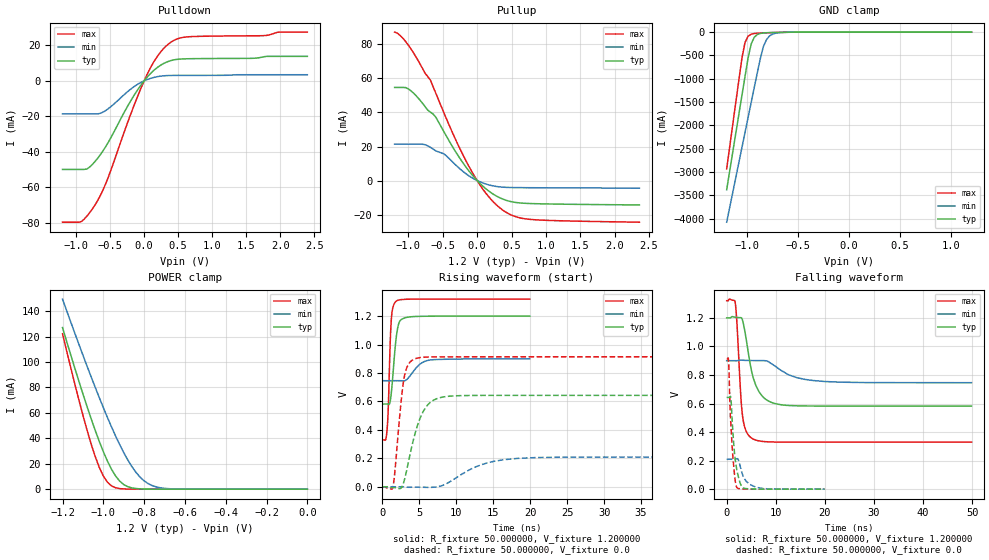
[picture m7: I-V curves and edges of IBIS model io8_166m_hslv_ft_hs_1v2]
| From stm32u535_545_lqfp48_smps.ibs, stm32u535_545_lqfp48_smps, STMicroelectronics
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|   Model io8_166m_hslv_ft_hs_1v2
[Model]  io8_166m_hslv_ft_hs_1v2
Model_type I/O
Polarity   Non-Inverting
Enable   Active-Low
Vinl =   0.360000V
Vinh =   0.840000V
Vmeas =  0.600000V
Cref =   50.000000pF
Rref =   100.000000M
Vref =   0.0V
C_comp   3.151700pF   3.087200pF   3.197900pF
[Temperature Range]   25.000000   0.140000k   -40.000000
[Pullup Reference]   1.200000V   0.900000V   1.320000V
[Pulldown Reference]   0.0V   0.0V   0.0V
[POWER Clamp Reference]   1.200000V   0.900000V   1.320000V
[GND Clamp Reference]   0.0V   0.0V   0.0V
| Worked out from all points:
|   slope of the pulldown table from 0 to 0.18 V, typ, clamps not added: 25.4 ohm
|   slope of the pullup table from 0 to 0.18 V, typ, clamps not added: 27.8 ohm
|   GND clamp passes 1 mA (typ) near -0.51 V on its own axis
|   POWER clamp passes 1 mA (typ) near -0.86 V on its own axis
|   rising waveform, R_fixture 50.000000, V_fixture 1.200000: 20-80 % time 648ps typ, 1.58ns min, 370ps max; typ from 0.582 V to 1.2 V
|   rising waveform, R_fixture 50.000000, V_fixture 0.0: 20-80 % time 2.05ns typ, 4.82ns min, 1.01ns max; typ from 0 V to 0.643 V
|   falling waveform, R_fixture 50.000000, V_fixture 1.200000: 20-80 % time 2.39ns typ, 5.33ns min, 1.03ns max; typ from 1.2 V to 0.582 V
|   falling waveform, R_fixture 50.000000, V_fixture 0.0: 20-80 % time 1.04ns typ, 1.73ns min, 825ps max; typ from 0.643 V to 0 V
[Pulldown]
|Voltage   I(typ)   I(min)   I(max)
-1.2V     -49.86mA   -18.57mA   -79.57mA
-920mV    -49.86mA   -18.57mA   -79.2mA
-840mV    -49.6mA    -18.57mA   -76.08mA
-720mV    -45.32mA   -18.57mA   -69.74mA
-560mV    -36.71mA   -16.58mA   -57.44mA
-200mV    -11.43mA   -4.74mA    -19.03mA
0V        10fA       -600fA     0A
160mV     6.477mA    2.075mA    11.78mA
360mV     10.99mA    2.99mA     20.81mA
480mV     12.07mA    3.054mA    23.53mA
640mV     12.43mA    3.075mA    24.76mA
2.4V      13.79mA    3.434mA    27.44mA
[Pullup]
|Voltage   I(typ)   I(min)   I(max)
-1.2V     54.73mA    21.36mA    87.24mA
-1.04V    54.63mA    21.36mA    81.73mA
-880mV    49.52mA    21.36mA    72.02mA
-680mV    40.23mA    19.54mA    59.03mA
-600mV    37.18mA    17.44mA    51.24mA
-480mV    28.49mA    15.58mA    39.53mA
-80mV     3.667mA    1.75mA     5.47mA
120mV     -4.592mA   -1.936mA   -7.077mA
360mV     -10.68mA   -3.85mA    -16.99mA
560mV     -12.87mA   -4.135mA   -21.24mA
760mV     -13.48mA   -4.204mA   -22.78mA
2.36V     -14.3mA    -4.5mA     -24.47mA
[GND_clamp]
|Voltage   I(typ)   I(min)   I(max)
-1.2V     -3.379A    -4.076A    -2.932A
-1.05V    -1.35A     -2.47A     -550.7mA
-1.02V    -947.8mA   -2.149A    -221.5mA
-990mV    -552.4mA   -1.829A    -88.44mA
-960mV    -255.3mA   -1.51A     -44.87mA
-930mV    -111.8mA   -1.191A    -30.68mA
-870mV    -28.36mA   -564.6mA   -21.34mA
-840mV    -18.65mA   -309.5mA   -18.49mA
-810mV    -14.07mA   -161.6mA   -15.92mA
-780mV    -11.37mA   -83.33mA   -13.53mA
-600mV    -3.009mA   -4.322mA   -3.091mA
1.2V      0A         13.65nA    0A
[POWER_clamp]
|Voltage   I(typ)   I(min)   I(max)
-1.2V     127mA      149.4mA    122.2mA
-1.12V    84.97mA    114mA      70.27mA
-1.06V    55.51mA    88.42mA    35.67mA
-1.02V    37.63mA    72.04mA    17.17mA
-1V       29.51mA    64.13mA    10.3mA
-960mV    15.69mA    48.99mA    2.571mA
-900mV    3.624mA    28.77mA    182.8uA
-840mV    490.7uA    13.24mA    11.35uA
-800mV    116.8uA    6.532mA    1.77uA
-740mV    13.2uA     1.723mA    109.1nA
-620mV    167.4nA    79.36uA    0A
0V        0A         17.87nA    0A
[Ramp]
| variable   typ   min   max
dV/dt_r  0.38563/2.04306n   0.12552/4.81423n   0.54825/1.00546n
dV/dt_f  0.37085/2.38517n   92.45400m/5.32112n  0.59438/1.02338n
R_load = 50.000000
[Rising Waveform]
R_fixture= 50.000000
V_fixture= 1.200000
V_fixture_min= 0.900000
V_fixture_max= 1.320000
|time   V(typ)   V(min)   V(max)
0s        582mV      745.9mV    329.5mV
600.6ps   582.3mV    745.9mV    380.1mV
800.8ps   580.3mV    745.9mV    552.7mV
1.041ns   595.9mV    745.9mV    982mV
1.201ns   654.6mV    745.9mV    1.167V
1.842ns   1.035V     746.1mV    1.304V
2.322ns   1.161V     746mV      1.314V
3.443ns   1.193V     761.4mV    1.319V
6.527ns   1.2V       892.3mV    1.32V
19.94ns   1.2V       900mV      1.32V
[Rising Waveform]
R_fixture= 50.000000
V_fixture= 0.0
V_fixture_min= 0.0
V_fixture_max= 0.0
|time   V(typ)   V(min)   V(max)
0s        -6.991uV   -235.1nV   -35.94uV
1.401ns   -6.349mV   -19.82uV   -8.306mV
2.903ns   33.74mV    -510.6uV   754.6mV
3.504ns   168.4mV    -3.227mV   859mV
4.605ns   406.8mV    -2.363mV   903.1mV
6.206ns   580mV      -4.033mV   912.6mV
8.909ns   636.1mV    28.58mV    913.7mV
13.41ns   642.5mV    155.5mV    913.8mV
18.22ns   642.8mV    199.4mV    913.9mV
49.85ns   642.9mV    209.3mV    913.9mV
[Falling Waveform]
R_fixture= 50.000000
V_fixture= 1.200000
V_fixture_min= 0.900000
V_fixture_max= 1.320000
|time   V(typ)   V(min)   V(max)
0s        1.2V       900mV      1.32V
1.702ns   1.204V     899.9mV    1.315V
2.002ns   1.203V     899.6mV    1.207V
3.203ns   1.187V     903.3mV    520.1mV
3.904ns   1.065V     902.1mV    411.5mV
5.305ns   794.1mV    900.9mV    352.9mV
7.307ns   649.4mV    900.4mV    334.4mV
11.21ns   590.6mV    829.3mV    329.8mV
19.92ns   582.1mV    754.2mV    329.5mV
49.85ns   582mV      745.9mV    329.5mV
[Falling Waveform]
R_fixture= 50.000000
V_fixture= 0.0
V_fixture_min= 0.0
V_fixture_max= 0.0
|time   V(typ)   V(min)   V(max)
0s        642.9mV    209.3mV    913.9mV
400.4ps   642.8mV    209.4mV    885.5mV
680.7ps   647.3mV    209.4mV    574mV
840.8ps   642.2mV    209.4mV    464mV
1.161ns   456.8mV    209.4mV    274.3mV
1.481ns   298.1mV    209.2mV    142.7mV
2.082ns   132.9mV    213.3mV    10.98mV
3.163ns   14.33mV    109.4mV    1.821mV
5.646ns   1.118mV    18.71mV    184.9uV
19.94ns   -6.991uV   -235.1nV   -35.94uV
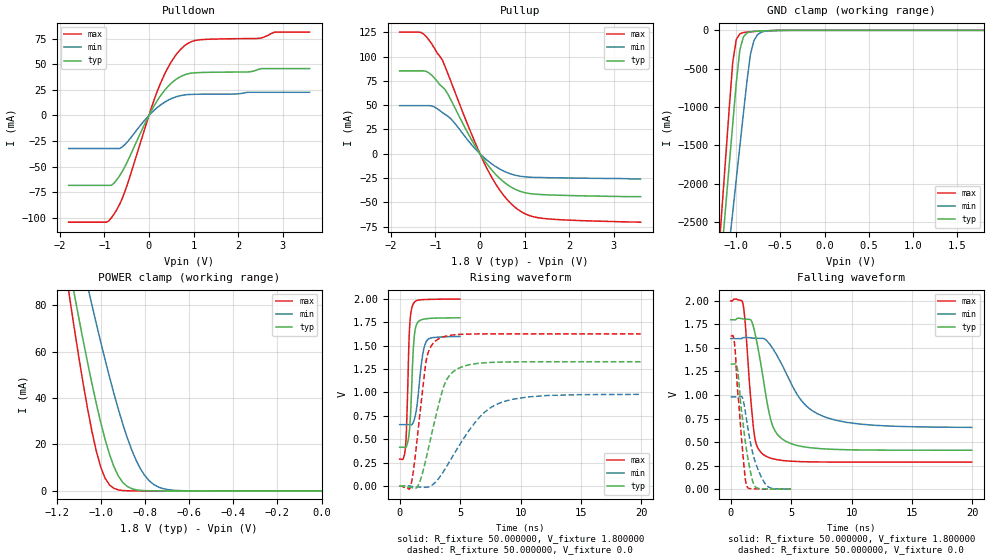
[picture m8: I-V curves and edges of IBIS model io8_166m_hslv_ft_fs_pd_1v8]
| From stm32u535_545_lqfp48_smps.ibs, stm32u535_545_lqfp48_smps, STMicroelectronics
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|   Model io8_166m_hslv_ft_fs_pd_1v8
[Model]  io8_166m_hslv_ft_fs_pd_1v8
Model_type I/O
Polarity   Non-Inverting
Enable   Active-Low
Vinl =   0.540000V
Vinh =   1.260000V
Vmeas =  0.900000V
Cref =   50.000000pF
Rref =   100.000000M
Vref =   0.0V
C_comp   3.358400pF   3.352800pF   3.400400pF
[Temperature Range]   25.000000   0.140000k   -40.000000
[Pullup Reference]   1.800000V   1.600000V   2.000000V
[Pulldown Reference]   0.0V   0.0V   0.0V
[POWER Clamp Reference]   1.800000V   1.600000V   2.000000V
[GND Clamp Reference]   0.0V   0.0V   0.0V
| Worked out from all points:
|   slope of the pulldown table from 0 to 0.27 V, typ, clamps not added: 13.6 ohm
|   slope of the pullup table from 0 to 0.27 V, typ, clamps not added: 15.9 ohm
|   GND clamp passes 1 mA (typ) near -0.50 V on its own axis
|   POWER clamp passes 1 mA (typ) near -0.86 V on its own axis
|   rising waveform, R_fixture 50.000000, V_fixture 1.800000: 20-80 % time 290ps typ, 498ps min, 237ps max; typ from 0.414 V to 1.8 V
|   rising waveform, R_fixture 50.000000, V_fixture 0.0: 20-80 % time 1.51ns typ, 3.17ns min, 854ps max; typ from 0 V to 1.33 V
|   falling waveform, R_fixture 50.000000, V_fixture 1.800000: 20-80 % time 1.2ns typ, 2.76ns min, 638ps max; typ from 1.8 V to 0.414 V
|   falling waveform, R_fixture 50.000000, V_fixture 0.0: 20-80 % time 787ps typ, 1.05ns min, 589ps max; typ from 1.33 V to 0 V
[Pulldown]
|Voltage   I(typ)   I(min)   I(max)
-1.8V     -68.38mA   -32.32mA   -104.4mA
-960mV    -68.38mA   -32.32mA   -104.4mA
-780mV    -66.08mA   -32.32mA   -96.43mA
-540mV    -50.22mA   -28.51mA   -74.66mA
0V        -10fA      -300fA     0A
240mV     18.04mA    9.6mA      29.42mA
480mV     30.68mA    16.02mA    50.95mA
780mV     39.48mA    19.99mA    67.56mA
1.14V     41.99mA    20.78mA    74.01mA
2.46V     45.09mA    22.7mA     75.45mA
2.82V     45.91mA    22.7mA     81.58mA
3.6V      45.91mA    22.7mA     81.58mA
[Pullup]
|Voltage   I(typ)   I(min)   I(max)
-1.8V     85.36mA    49.56mA    125.3mA
-1.32V    85.36mA    49.56mA    124.9mA
-1.08V    80.86mA    49.29mA    113.1mA
-840mV    68.71mA    42.35mA    96.4mA
-660mV    56.31mA    36.43mA    75.51mA
-180mV    13.77mA    8.913mA    19.32mA
180mV     -11.9mA    -7.442mA   -17.26mA
480mV     -26.98mA   -16.65mA   -39.76mA
840mV     -37.65mA   -22.63mA   -57.07mA
1.08V     -40.74mA   -24.01mA   -63.22mA
1.44V     -42.19mA   -24.58mA   -66.73mA
3.6V      -44.2mA    -26mA      -70.5mA
[GND_clamp]
|Voltage   I(typ)   I(min)   I(max)
-1.8V     -9.908A    -9.683A    -9.994A
-1.2V     -3.383A    -4.084A    -2.934A
-1.16V    -2.841A    -3.655A    -2.294A
-1.12V    -2.299A    -3.226A    -1.656A
-1.04V    -1.218A    -2.369A    -414.2mA
-1V       -684.7mA   -1.941A    -119.2mA
-960mV    -257.2mA   -1.514A    -45.67mA
-920mV    -87.04mA   -1.089A    -28.94mA
-840mV    -19.36mA   -312.8mA   -18.98mA
-800mV    -13.56mA   -132.4mA   -15.51mA
-720mV    -8.053mA   -25.67mA   -9.505mA
1.8V      45.71uA    33.32uA    56.11uA
[POWER_clamp]
|Voltage   I(typ)   I(min)   I(max)
-1.8V     470.8mA    433.7mA    554.6mA
-1.14V    95.25mA    122.7mA    82.82mA
-1.12V    84.97mA    114mA      70.27mA
-1.06V    55.51mA    88.42mA    35.67mA
-1.04V    46.34mA    80.15mA    25.76mA
-1V       29.51mA    64.13mA    10.3mA
-940mV    10.39mA    41.86mA    1.109mA
-900mV    3.624mA    28.77mA    182.8uA
-840mV    490.7uA    13.24mA    11.35uA
-800mV    116.8uA    6.532mA    1.77uA
-740mV    13.2uA     1.724mA    109.3nA
0V        0A         18.75nA    0A
[Ramp]
| variable   typ   min   max
dV/dt_r  0.79740/1.50689n   0.58757/3.16119n   0.97632/0.85214n
dV/dt_f  0.83143/1.19779n   0.56477/2.75329n   1.02744/0.63651n
R_load = 50.000000
[Rising Waveform]
R_fixture= 50.000000
V_fixture= 1.800000
V_fixture_min= 1.600000
V_fixture_max= 2.000000
|time   V(typ)   V(min)   V(max)
0s        413.8mV    656.4mV    287.2mV
500.5ps   412.6mV    656.6mV    437.2mV
590.6ps   432.9mV    656.6mV    694mV
810.8ps   591.3mV    655.3mV    1.658V
1.071ns   1.305V     665.1mV    1.931V
1.181ns   1.556V     697.5mV    1.96V
1.341ns   1.705V     782mV      1.979V
1.872ns   1.78V      1.374V     1.993V
2.192ns   1.789V     1.543V     1.995V
4.985ns   1.8V       1.599V     2V
[Rising Waveform]
R_fixture= 50.000000
V_fixture= 0.0
V_fixture_min= 0.0
V_fixture_max= 0.0
|time   V(typ)   V(min)   V(max)
0s        -26.74uV   -4.216uV   -6.929uV
920.9ps   -14.89mV   -1.619mV   3.04mV
1.562ns   13.81mV    -10.95mV   633.6mV
2.202ns   299.1mV    -14.1mV    1.344V
3.123ns   814.5mV    62.59mV    1.566V
3.764ns   1.102V     182.9mV    1.601V
4.484ns   1.227V     338.3mV    1.617V
6.607ns   1.313V     734.4mV    1.626V
8.368ns   1.325V     891.6mV    1.627V
19.94ns   1.329V     979.8mV    1.627V
[Falling Waveform]
R_fixture= 50.000000
V_fixture= 1.800000
V_fixture_min= 1.600000
V_fixture_max= 2.000000
|time   V(typ)   V(min)   V(max)
0s        1.8V       1.599V     2V
1.001ns   1.809V     1.608V     1.979V
1.161ns   1.806V     1.612V     1.825V
1.962ns   1.685V     1.605V     574.7mV
2.763ns   1.118V     1.598V     362.6mV
3.323ns   733.9mV    1.524V     329.2mV
3.924ns   573.4mV    1.399V     311.7mV
5.846ns   454.6mV    942.3mV    292.2mV
7.848ns   427.2mV    764.1mV    288.3mV
19.94ns   413.8mV    656.4mV    287.2mV
[Falling Waveform]
R_fixture= 50.000000
V_fixture= 0.0
V_fixture_min= 0.0
V_fixture_max= 0.0
|time   V(typ)   V(min)   V(max)
0s        1.329V     979.8mV    1.627V
290.3ps   1.329V     979.9mV    1.575V
400.4ps   1.334V     979.9mV    1.427V
530.5ps   1.299V     979.9mV    1.128V
981ps     749.6mV    969.6mV    418.7mV
1.191ns   523.1mV    839.3mV    129.9mV
1.351ns   385.9mV    706.8mV    28.12mV
1.952ns   41.28mV    324.5mV    2.701mV
2.773ns   2.905mV    73.12mV    1.023mV
4.985ns   -26.74uV   -4.216uV   -6.929uV
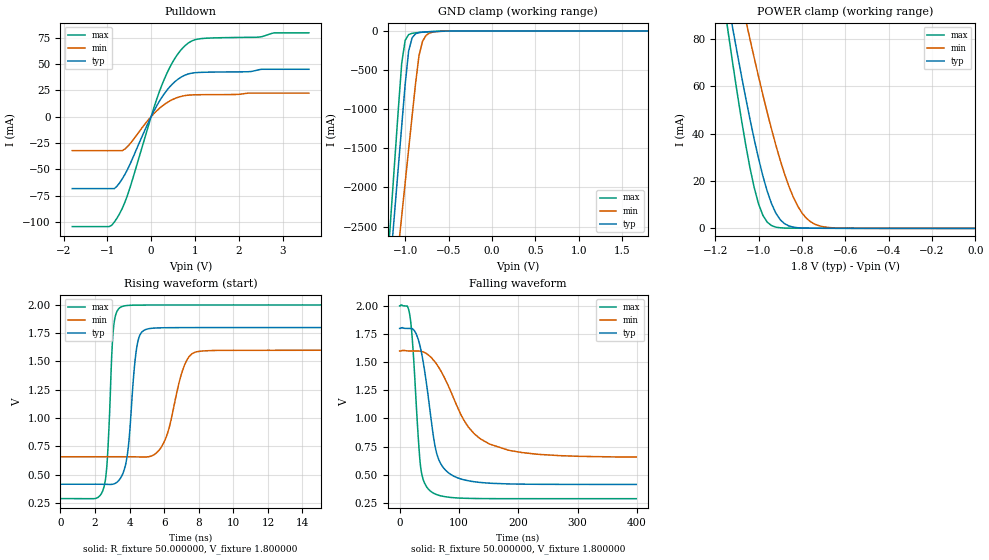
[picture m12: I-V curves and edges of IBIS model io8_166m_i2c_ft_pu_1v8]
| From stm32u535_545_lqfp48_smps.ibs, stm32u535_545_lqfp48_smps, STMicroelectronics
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|   Model io8_166m_i2c_ft_pu_1v8
[Model]  io8_166m_i2c_ft_pu_1v8
Model_type I/O_open_drain
Polarity   Non-Inverting
Enable   Active-Low
Vinl =   0.540000V
Vinh =   1.260000V
Vmeas =  0.900000V
Cref =   50.000000pF
Rref =   100.000000M
Vref =   0.900000V
C_comp   3.364500pF   3.359200pF   3.406800pF
[Temperature Range]   25.000000   0.140000k   -40.000000
[Pullup Reference]   1.800000V   1.600000V   2.000000V
[Pulldown Reference]   0.0V   0.0V   0.0V
[POWER Clamp Reference]   1.800000V   1.600000V   2.000000V
[GND Clamp Reference]   0.0V   0.0V   0.0V
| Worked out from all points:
|   slope of the pulldown table from 0 to 0.27 V, typ, clamps not added: 13.6 ohm
|   GND clamp passes 1 mA (typ) near -0.51 V on its own axis
|   POWER clamp passes 1 mA (typ) near -0.86 V on its own axis
|   rising waveform, R_fixture 50.000000, V_fixture 1.800000: 20-80 % time 442ps typ, 895ps min, 292ps max; typ from 0.414 V to 1.8 V
|   falling waveform, R_fixture 50.000000, V_fixture 1.800000: 20-80 % time 23.4ns typ, 59.2ns min, 12.2ns max; typ from 1.8 V to 0.414 V
[Pulldown]
|Voltage   I(typ)   I(min)   I(max)
-1.8V     -68.38mA   -32.32mA   -104.4mA
-960mV    -68.38mA   -32.32mA   -104.4mA
-780mV    -66.08mA   -32.32mA   -96.43mA
-660mV    -59.2mA    -32.31mA   -87.22mA
-540mV    -50.22mA   -28.51mA   -74.66mA
0V        0A         0A         0A
240mV     18.04mA    9.6mA      29.42mA
480mV     30.68mA    16.02mA    50.95mA
780mV     39.48mA    19.99mA    67.56mA
1.14V     41.99mA    20.78mA    74.01mA
2.82V     44.92mA    22.27mA    79.53mA
3.6V      44.92mA    22.27mA    79.53mA
[GND_clamp]
|Voltage   I(typ)   I(min)   I(max)
-1.8V     -9.908A    -9.683A    -9.994A
-1.2V     -3.383A    -4.084A    -2.934A
-1.16V    -2.841A    -3.655A    -2.294A
-1.12V    -2.299A    -3.226A    -1.656A
-1.04V    -1.218A    -2.369A    -414.2mA
-1V       -684.7mA   -1.941A    -119.2mA
-960mV    -257.2mA   -1.514A    -45.66mA
-920mV    -87.03mA   -1.089A    -28.93mA
-840mV    -19.35mA   -312.8mA   -18.97mA
-800mV    -13.55mA   -132.4mA   -15.49mA
-720mV    -8.042mA   -25.67mA   -9.491mA
1.8V      0A         13.64nA    0A
[POWER_clamp]
|Voltage   I(typ)   I(min)   I(max)
-1.8V     470.9mA    433.7mA    554.6mA
-1.14V    95.28mA    122.7mA    82.88mA
-1.12V    85mA       114mA      70.34mA
-1.06V    55.55mA    88.43mA    35.73mA
-1.04V    46.38mA    80.17mA    25.83mA
-1V       29.54mA    64.14mA    10.37mA
-940mV    10.43mA    41.88mA    1.177mA
-900mV    3.66mA     28.79mA    250.6uA
-840mV    527.3uA    13.26mA    96.04uA
-800mV    154uA      6.55mA     88.41uA
-740mV    59.84uA    1.741mA    70.38uA
0V        0A         18.18nA    0A
[Ramp]
| variable   typ   min   max
dV/dt_r  0.83121/0.44362n   0.56539/0.89338n   1.02737/0.29186n
dV/dt_f  0.83133/23.35115n   0.56457/59.23377n   1.02743/12.16973n
R_load = 50.000000
[Rising Waveform]
R_fixture= 50.000000
V_fixture= 1.800000
V_fixture_min= 1.600000
V_fixture_max= 2.000000
|time   V(typ)   V(min)   V(max)
0s        414.4mV    657.5mV    287.6mV
2.482ns   414.1mV    657.5mV    373mV
2.723ns   413.2mV    657.5mV    661.7mV
3.083ns   416.8mV    657.5mV    1.817V
3.483ns   471.2mV    657.5mV    1.98V
3.924ns   739.7mV    657.3mV    1.996V
4.404ns   1.615V     656.3mV    1.998V
4.885ns   1.78V      655mV      1.999V
7.808ns   1.8V       1.583V     2V
19.94ns   1.8V       1.6V       2V
[Falling Waveform]
R_fixture= 50.000000
V_fixture= 1.800000
V_fixture_min= 1.600000
V_fixture_max= 2.000000
|time   V(typ)   V(min)   V(max)
0s        1.8V       1.6V       2V
16.82ns   1.8V       1.6V       1.93V
21.62ns   1.797V     1.6V       1.685V
35.24ns   1.624V     1.597V     576mV
52.05ns   1.034V     1.548V     354.5mV
61.66ns   706mV      1.488V     325.6mV
74.47ns   558.4mV    1.374V     307.5mV
115.3ns   447.6mV    927.9mV    290.6mV
151.4ns   425.5mV    773.4mV    288.2mV
398.8ns   414.4mV    657.5mV    287.6mV
